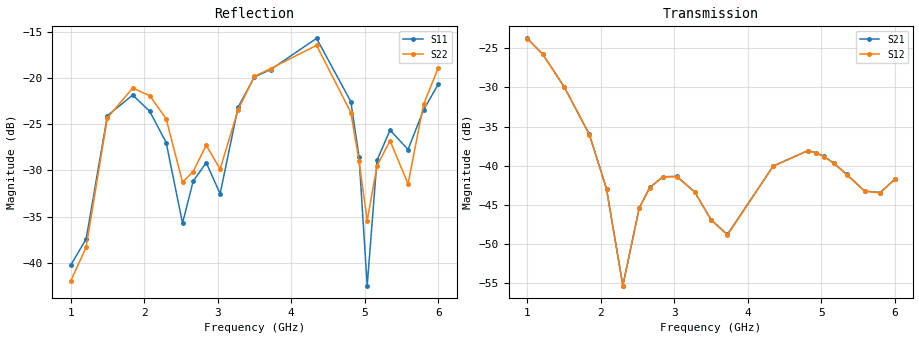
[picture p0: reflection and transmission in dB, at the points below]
!Agilent Technologies,E8364B,MY43040528,A.07.50.67
!Agilent E8364B: A.07.50.67
!Date: Sunday, March 01, 2026 21:22:52
!Correction: S11(Full 2 Port(1,2))
!S21(Full 2 Port(1,2))
!S12(Full 2 Port(1,2))
!S22(Full 2 Port(1,2))
!S2P File: Measurements: S11, S21, S12, S22:
# Hz S  dB  R 50
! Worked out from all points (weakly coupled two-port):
!   451 points, 1 GHz to 6 GHz, reference 50 ohm
!   highest |S21| = -23.76 dB at 1 GHz (marker M1); lowest = -55.3 dB at 2.3 GHz (marker M2)
!   lowest |S11| = -42.5 dB at 5.033 GHz (marker M3), VSWR 1.02, Z = 50.1 - j0.746 ohm
!   |S11| at or under -10 dB: start of sweep to end of sweep
!   |S22| runs from -43.5 to -16.0 dB; largest |S21 - S12| = 0.00022
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1e9  -40.30 83.1  -23.76 148.5  -23.79 148.5  -42.02 24.6
1.211111e9  -37.45 150.3  -25.78 26.6  -25.81 26.6  -38.35 94.9
1.5e9  -24.06 147.6  -29.90 -135.6  -29.92 -135.6  -24.30 75.2
1.844444e9  -21.82 86.8  -36.00 38.0  -36.04 38.0  -21.06 -5.7
2.077778e9  -23.60 57.1  -42.94 -84.9  -42.97 -85.0  -21.90 -49.2
2.3e9  -26.98 32.5  -55.28 -132.1  -55.30 -132.2  -24.39 -87.6
2.522222e9  -35.72 50.5  -45.40 171.5  -45.44 171.5  -31.27 -99.9
2.666667e9  -31.17 82.5  -42.76 95.8  -42.79 95.9  -30.12 -71.7
2.844444e9  -29.15 64.5  -41.41 -0.0  -41.46 -0.0  -27.27 -89.4
3.033333e9  -32.53 80.2  -41.36 -102.9  -41.40 -102.8  -29.86 -95.4
3.277778e9  -23.14 93.6  -43.34 126.9  -43.38 127.0  -23.42 -82.1
3.5e9  -19.85 60.8  -46.89 22.3  -46.93 22.5  -19.79 -120.1
3.722222e9  -19.05 38.7  -48.77 -53.3  -48.84 -53.1  -18.95 -151.1
4.344444e9  -15.67 -40.7  -40.04 12.8  -40.07 12.9  -16.42 100.1
4.811111e9  -22.53 -121.1  -38.09 106.5  -38.12 106.5  -23.72 -1.7
4.922222e9  -28.50 -137.8  -38.32 40.4  -38.35 40.5  -28.96 -19.7
5.033333e9  -42.50 -83.0  -38.80 -26.1  -38.84 -26.1  -35.46 11.8
5.166667e9  -28.90 -33.7  -39.65 -107.1  -39.69 -107.1  -29.48 36.2
5.344444e9  -25.62 -60.2  -41.11 141.2  -41.15 141.2  -26.78 3.4
5.588889e9  -27.73 -61.0  -43.23 -25.8  -43.27 -25.7  -31.45 7.1
5.8e9  -23.43 -55.3  -43.42 -179.6  -43.46 -179.6  -22.83 11.2
6e9  -20.64 -74.6  -41.70 41.3  -41.73 41.4  -18.87 -25.9
